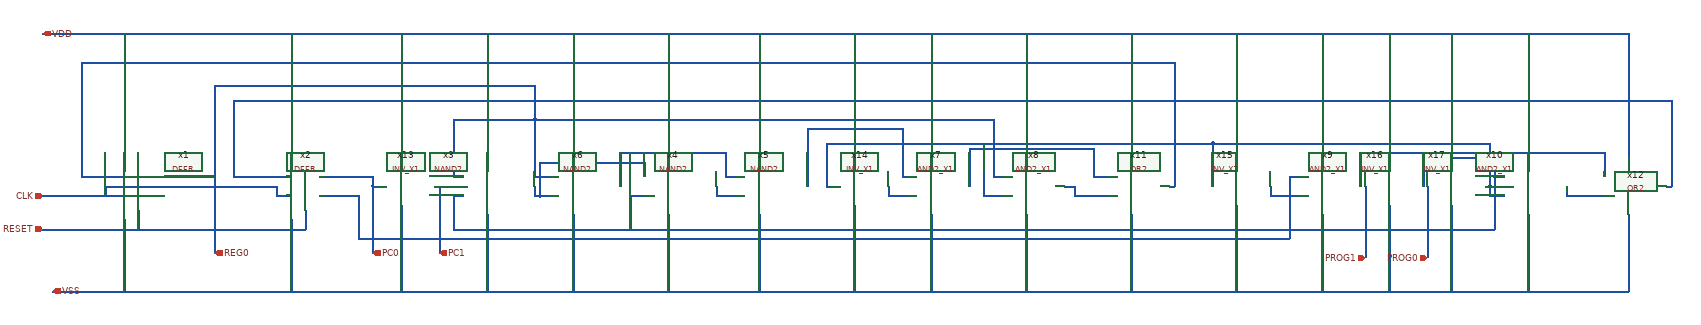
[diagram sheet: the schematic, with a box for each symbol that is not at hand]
v {xschem version=3.4.8RC file_version=1.2}
G {}
K {}
V {}
S {}
E {}
N -523810 -1425020 -523730 -1425020 {
lab=#net1}
N -523810 -1425040 -523810 -1425020 {
lab=#net1}
N -524000 -1425110 -523730 -1425110 {
lab=#net2}
N -524140 -1425110 -524000 -1425110 {
lab=#net2}
N -524240 -1425110 -524140 -1425110 {
lab=#net2}
N -524240 -1425110 -524240 -1425040 {
lab=#net2}
N -524430 -1425040 -524430 -1425020 {
lab=#net3}
N -523960 -1425080 -523960 -1425060 {
lab=#net4}
N -524360 -1425130 -523980 -1425130 {
lab=#net5}
N -524550 -1425130 -524550 -1425040 {
lab=#net5}
N -524550 -1425130 -524360 -1425130 {
lab=#net5}
N -524840 -1425020 -524770 -1425020 {
lab=#net6}
N -524840 -1425040 -524840 -1425020 {
lab=#net6}
N -524800 -1425060 -524770 -1425060 {
lab=#net7}
N -525200 -1425140 -525200 -1425060 {
lab=#net8}
N -525230 -1425040 -525230 -1425020 {
lab=#net9}
N -525360 -1425130 -524550 -1425130 {
lab=#net5}
N -525360 -1425130 -525360 -1425040 {
lab=#net5}
N -525030 -1425130 -525030 -1425020 {
lab=#net5}
N -525030 -1425020 -524990 -1425020 {
lab=#net5}
N -525010 -1425060 -524990 -1425060 {
lab=reg0}
N -524800 -1425100 -524800 -1425060 {
lab=#net7}
N -525060 -1425100 -525060 -1425040 {
lab=#net7}
N -525200 -1425160 -525200 -1425140 {
lab=#net8}
N -525770 -1425020 -525740 -1425020 {
lab=#net4}
N -525770 -1425020 -525770 -1424980 {
lab=#net4}
N -525570 -1425110 -525570 -1425060 {
lab=#net10}
N -525740 -1425090 -525740 -1425060 {
lab=#net11}
N -525960 -1425090 -525740 -1425090 {
lab=#net11}
N -526530 -1425250 -525970 -1425250 {
lab=reg0}
N -526140 -1425020 -526120 -1425020 {
lab=#net4}
N -526140 -1425020 -526140 -1424980 {
lab=#net4}
N -526140 -1425060 -526120 -1425060 {
lab=reg0}
N -526140 -1425180 -526140 -1425060 {
lab=reg0}
N -526140 -1425180 -525970 -1425180 {
lab=reg0}
N -525970 -1425180 -525010 -1425180 {
lab=reg0}
N -525010 -1425180 -525010 -1425060 {
lab=reg0}
N -523960 -1425060 -523960 -1424980 {
lab=#net4}
N -526170 -1425040 -526170 -1424900 {
lab=PC1}
N -526310 -1425040 -526310 -1424900 {
lab=PC0}
N -526360 -1425060 -526310 -1425060 {
lab=PC0}
N -526310 -1425060 -526310 -1425040 {
lab=PC0}
N -524390 -1425060 -524390 -1424960 {
lab=#net12}
N -526600 -1425220 -523600 -1425220 {
lab=#net13}
N -523590 -1425220 -523590 -1425040 {
lab=#net13}
N -523600 -1425220 -523590 -1425220 {
lab=#net13}
N -526640 -1425050 -526640 -1424920 {
lab=reg0}
N -526640 -1425250 -526640 -1425050 {
lab=reg0}
N -526640 -1425250 -526530 -1425250 {
lab=reg0}
N -526920 -1425300 -524650 -1425300 {
lab=#net14}
N -524630 -1425300 -524630 -1425040 {
lab=#net14}
N -524650 -1425300 -524630 -1425300 {
lab=#net14}
N -526670 -1425060 -526640 -1425060 {
lab=reg0}
N -523730 -1425110 -523730 -1425060 {
lab=#net2}
N -526770 -1425060 -526670 -1425060 {lab=reg0}
N -526920 -1425060 -526830 -1425060 {lab=#net14}
N -526920 -1425300 -526920 -1425060 {lab=#net14}
N -527000 -1425020 -526830 -1425020 {lab=CLK}
N -526420 -1425060 -526360 -1425060 {lab=PC0}
N -526420 -1425020 -526340 -1425020 {lab=#net12}
N -526340 -1425020 -526340 -1424960 {lab=#net12}
N -526600 -1425060 -526480 -1425060 {lab=#net13}
N -526600 -1425220 -526600 -1425060 {lab=#net13}
N -526510 -1425020 -526480 -1425020 {lab=CLK}
N -526510 -1425040 -526510 -1425020 {lab=CLK}
N -526870 -1425040 -526510 -1425040 {lab=CLK}
N -526870 -1425040 -526870 -1425020 {lab=CLK}
N -527000 -1424950 -526450 -1424950 {lab=RESET}
N -526450 -1424990 -526450 -1424950 {lab=RESET}
N -526800 -1424990 -526800 -1424950 {lab=RESET}
N -526640 -1424920 -526640 -1424900 {lab=reg0}
N -526310 -1425040 -526300 -1425040 {lab=PC0}
N -526180 -1425040 -526170 -1425040 {lab=PC1}
N -525570 -1425060 -525550 -1425060 {lab=#net10}
N -525200 -1425060 -525190 -1425060 {lab=#net8}
N -525230 -1425020 -525190 -1425020 {lab=#net9}
N -524860 -1425040 -524840 -1425040 {lab=#net6}
N -523960 -1425060 -523940 -1425060 {lab=#net4}
N -524430 -1425020 -524370 -1425020 {lab=#net3}
N -524390 -1425060 -524370 -1425060 {lab=#net12}
N -524640 -1425040 -524630 -1425040 {lab=#net14}
N -523600 -1425040 -523590 -1425040 {lab=#net13}
N -524230 -1425040 -524230 -1424890 {lab=PC0}
N -524100 -1425040 -524100 -1424890 {lab=PC1}
N -524110 -1425080 -524110 -1425040 {lab=#net4}
N -523980 -1425040 -523970 -1425040 {lab=#net5}
N -523970 -1425040 -523970 -1425020 {lab=#net5}
N -523970 -1425020 -523940 -1425020 {lab=#net5}
N -523970 -1425130 -523970 -1425040 {lab=#net5}
N -523980 -1425130 -523970 -1425130 {lab=#net5}
N -524390 -1424960 -524390 -1424930 {lab=#net12}
N -526340 -1424930 -524390 -1424930 {lab=#net12}
N -526340 -1424960 -526340 -1424930 {lab=#net12}
N -526140 -1424980 -526140 -1424950 {lab=#net4}
N -526140 -1424950 -523960 -1424950 {lab=#net4}
N -523960 -1424980 -523960 -1424950 {lab=#net4}
N -524110 -1425100 -524110 -1425080 {lab=#net4}
N -524110 -1425100 -523960 -1425100 {lab=#net4}
N -523960 -1425100 -523960 -1425080 {lab=#net4}
N -525770 -1424980 -525770 -1424950 {lab=#net4}
N -523680 -1425360 -523680 -1425100 {lab=VDD}
N -527000 -1425360 -523680 -1425360 {lab=VDD}
N -526980 -1424820 -523680 -1424820 {lab=VSS}
N -523680 -1424980 -523680 -1424820 {lab=VSS}
N -523890 -1424980 -523890 -1424820 {lab=VSS}
N -524050 -1425000 -524050 -1424820 {lab=VSS}
N -524180 -1425000 -524180 -1424820 {lab=VSS}
N -524320 -1424980 -524320 -1424820 {lab=VSS}
N -524500 -1425000 -524500 -1424820 {lab=VSS}
N -524720 -1424980 -524720 -1424820 {lab=VSS}
N -524940 -1424980 -524940 -1424820 {lab=VSS}
N -525140 -1424980 -525140 -1424820 {lab=VSS}
N -525300 -1425000 -525300 -1424820 {lab=VSS}
N -525360 -1425040 -525350 -1425040 {lab=#net5}
N -526830 -1424970 -526830 -1424820 {lab=VSS}
N -526480 -1424970 -526480 -1424820 {lab=VSS}
N -526250 -1425000 -526250 -1424820 {lab=VSS}
N -526070 -1424980 -526070 -1424820 {lab=VSS}
N -525890 -1424980 -525890 -1424820 {lab=VSS}
N -525690 -1424980 -525690 -1424820 {lab=VSS}
N -525500 -1424980 -525500 -1424820 {lab=VSS}
N -526830 -1425360 -526830 -1425090 {lab=VDD}
N -526480 -1425360 -526480 -1425090 {lab=VDD}
N -526250 -1425360 -526250 -1425080 {lab=VDD}
N -526070 -1425360 -526070 -1425100 {lab=VDD}
N -525890 -1425360 -525890 -1425100 {lab=VDD}
N -525690 -1425360 -525690 -1425100 {lab=VDD}
N -525500 -1425360 -525500 -1425100 {lab=VDD}
N -525300 -1425360 -525300 -1425080 {lab=VDD}
N -525140 -1425360 -525140 -1425100 {lab=VDD}
N -524800 -1425120 -524800 -1425100 {lab=#net7}
N -525060 -1425120 -524800 -1425120 {lab=#net7}
N -525060 -1425120 -525060 -1425100 {lab=#net7}
N -524940 -1425360 -524940 -1425100 {lab=VDD}
N -524720 -1425360 -524720 -1425100 {lab=VDD}
N -524500 -1425360 -524500 -1425080 {lab=VDD}
N -524320 -1425360 -524320 -1425100 {lab=VDD}
N -524180 -1425360 -524180 -1425080 {lab=VDD}
N -524050 -1425360 -524050 -1425080 {lab=VDD}
N -523890 -1425360 -523890 -1425100 {lab=VDD}
N -525970 -1425250 -525970 -1425180 {lab=reg0}
N -525970 -1425180 -525970 -1425060 {lab=reg0}
N -525970 -1425060 -525940 -1425060 {lab=reg0}
N -525960 -1425090 -525960 -1425020 {lab=#net11}
N -525970 -1425040 -525970 -1425020 {lab=#net11}
N -525970 -1425020 -525960 -1425020 {lab=#net11}
N -525960 -1425020 -525940 -1425020 {lab=#net11}
N -525790 -1425110 -525790 -1425040 {lab=#net10}
N -525790 -1425110 -525570 -1425110 {lab=#net10}
N -525590 -1425040 -525590 -1425020 {lab=#net15}
N -525590 -1425020 -525550 -1425020 {lab=#net15}
N -525400 -1425160 -525400 -1425040 {lab=#net8}
N -525400 -1425160 -525200 -1425160 {lab=#net8}
C {IP62_5_stdcell/DFFR.sym} -526800 -1425030 0 0 {name=x1}
C {IP62_5_stdcell/DFFR.sym} -526450 -1425030 0 0 {name=x2}
C {IP62_5_stdcell/INV_X1.sym} -526280 -1425040 0 0 {name=x13}
C {IP62_5_stdcell/AND2_X1.sym} -525170 -1425040 0 0 {name=x7}
C {IP62_5_stdcell/AND2_X1.sym} -524970 -1425040 0 0 {name=x8}
C {IP62_5_stdcell/AND2_X1.sym} -524350 -1425040 0 0 {name=x9}
C {IP62_5_stdcell/AND2_X1.sym} -523920 -1425040 0 0 {name=x10}
C {IP62_5_stdcell/OR2.sym} -524750 -1425040 0 0 {name=x11}
C {IP62_5_stdcell/OR2.sym} -523710 -1425040 0 0 {name=x12}
C {IP62_5_stdcell/INV_X1.sym} -525330 -1425040 0 0 {name=x14}
C {IP62_5_stdcell/INV_X1.sym} -524530 -1425040 0 0 {name=x15}
C {IP62_5_stdcell/INV_X1.sym} -524210 -1425040 0 0 {name=x16}
C {IP62_5_stdcell/INV_X1.sym} -524080 -1425040 0 0 {name=x17}
C {IP62_5_stdcell/NAND2.sym} -526100 -1425040 0 0 {name=x3}
C {IP62_5_stdcell/NAND2.sym} -525720 -1425040 0 0 {name=x4}
C {IP62_5_stdcell/NAND2.sym} -525530 -1425040 0 0 {name=x5}
C {IP62_5_stdcell/NAND2.sym} -525920 -1425040 0 0 {name=x6}
C {devices/ipin.sym} -527000 -1425020 0 0 {name=p3 lab=CLK}
C {devices/ipin.sym} -527000 -1424950 0 0 {name=p4 lab=RESET}
C {devices/iopin.sym} -527000 -1425360 0 1 {name=p5 lab=VDD}
C {devices/iopin.sym} -526980 -1424820 0 1 {name=p6 lab=VSS}
C {devices/opin.sym} -526640 -1424900 1 0 {name=p18 lab=REG0}
C {devices/opin.sym} -526310 -1424900 1 0 {name=p1 lab=PC0}
C {devices/opin.sym} -526170 -1424900 1 0 {name=p8 lab=PC1}
C {devices/ipin.sym} -524230 -1424890 3 0 {name=p2 lab=PROG1}
C {devices/ipin.sym} -524100 -1424890 3 0 {name=p7 lab=PROG0}
